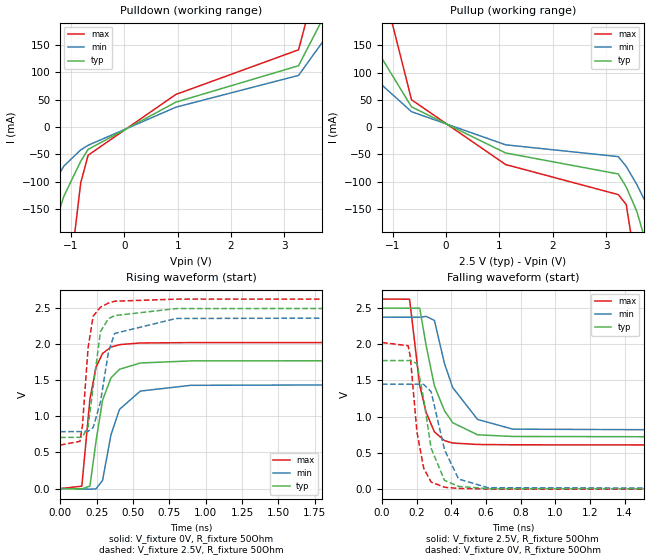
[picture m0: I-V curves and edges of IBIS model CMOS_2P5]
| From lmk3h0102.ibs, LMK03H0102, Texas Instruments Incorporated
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[Model]   CMOS_2P5
Model_type   Output
Polarity   Non-Inverting
Vmeas = 1.25
Vref = 0
Cref = 5pF
Rref = 100000
|   typ   min   max
C_comp   2.5pF   2pF   3pF
[Voltage Range]   2.5   2.375   2.625
[Temperature Range]   45   125   -40
[Pullup Reference]   2.5   2.375   2.625
[Pulldown Reference]   0   0   0
[Power Clamp Reference]   2.5   2.375   2.625
[GND Clamp Reference]   0   0   0
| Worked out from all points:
|   slope of the pulldown table from 0 to 0.375 V, typ, clamps not added: 18.7 ohm
|   slope of the pullup table from 0 to 0.375 V, typ, clamps not added: 19.6 ohm
|   falling waveform, V_fixture 2.5V, R_fixture 50Ohm: 20-80 % time 120ps typ, 157ps min, 83.9ps max; typ from 2.5 V to 0.708 V
|   rising waveform, V_fixture 0V, R_fixture 50Ohm: 20-80 % time 91.9ps typ, 118ps min, 70.2ps max; typ from 0 V to 1.77 V
|   rising waveform, V_fixture 2.5V, R_fixture 50Ohm: 20-80 % time 63.8ps typ, 86.2ps min, 48.1ps max; typ from 0.708 V to 2.5 V
|   falling waveform, V_fixture 0V, R_fixture 50Ohm: 20-80 % time 75.8ps typ, 91.7ps min, 57.9ps max; typ from 1.77 V to 0 V
[Pulldown]
|   Voltage   I(typ)   I(min)   I(max)
-3.3V     -897.3mA   -527.2mA   -2.687A
-2.221V   -519.5mA   -296.6mA   -1.529A
-1.34V    -191.4mA   -106.5mA   -555.5mA
-1.132V   -126.7mA   -71.27mA   -363.4mA
-815.1mV  -62.38mA   -41.6mA    -101.9mA
-676.5mV  -40.69mA   -33.18mA   -51.39mA
966.9mV   45.66mA    36.48mA    59.79mA
3.264V    112.3mA    94.6mA     141.4mA
3.749V    204.3mA    160.5mA    319.6mA
4.135V    293.1mA    223.3mA    516.9mA
5.402V    600.8mA    442.5mA    1.202A
6.6V      903.3mA    672mA      1.862A
[Pullup]
|   Voltage   I(typ)   I(min)   I(max)
-3.3V     606.4mA    421.4mA    1.361A
-2.538V   422.8mA    287mA      953.3mA
-1.825V   260mA      169.8mA    583.3mA
-1.181V   122.8mA    75.4mA     257.7mA
-646.8mV  37.13mA    28.31mA    50.19mA
1.115V    -47.36mA   -32.4mA    -68.56mA
3.224V    -85.87mA   -54.05mA   -123.7mA
3.373V    -109.6mA   -71.9mA    -141.8mA
3.571V    -154.2mA   -105.1mA   -264.3mA
3.937V    -277.2mA   -176.8mA   -616.1mA
4.749V    -584.9mA   -358mA     -1.516A
6.6V      -1.309A    -817.2mA   -3.598A
[Ramp]
R_load = 50
|   typ   min   max
dV/dt_r   1.06504/9.18916e-11   0.869589/1.17448e-10   1.21419/6.98564e-11
dV/dt_f   1.07469/1.19617e-10   0.951604/1.56694e-10   1.21291/8.3962e-11
[Falling Waveform]
V_fixture = 2.5V
V_fixture_min = 2.375V
V_fixture_max = 2.625V
R_fixture = 50Ohm
C_fixture = 0F
|   Time   V(typ)   V(min)   V(max)
0s        2.499V     2.374V     2.624V
159.3ps   2.498V     2.373V     2.622V
217.8ps   2.498V     2.373V     1.43V
255.2ps   1.977V     2.385V     1.057V
302.6ps   1.425V     2.329V     790.7mV
360.5ps   1.084V     1.734V     670.3mV
408.2ps   917.3mV    1.402V     636.8mV
551.5ps   750.2mV    962.5mV    617mV
755ps     727.4mV    828.3mV    612.3mV
5ns       707.9mV    787.7mV    602.6mV
[Rising Waveform]
V_fixture = 0V
V_fixture_min = 0V
V_fixture_max = 0V
R_fixture = 50Ohm
C_fixture = 0F
|   Time   V(typ)   V(min)   V(max)
0s        114.4uV    4.884uV    29.28uV
149ps     -4.508mV   -5.851mV   33.74mV
204.7ps   34.28mV    -8.041mV   1.238V
246.5ps   655.1mV    -3.982mV   1.681V
291.5ps   1.223V     112.2mV    1.871V
349.3ps   1.533V     744.1mV    1.959V
408.2ps   1.652V     1.097V     1.993V
551.5ps   1.739V     1.35V      2.016V
899.5ps   1.768V     1.43V      2.021V
5ns       1.775V     1.449V     2.024V
[Rising Waveform]
V_fixture = 2.5V
V_fixture_min = 2.375V
V_fixture_max = 2.625V
R_fixture = 50Ohm
C_fixture = 0F
|   Time   V(typ)   V(min)   V(max)
0s        707.9mV    787.8mV    602.6mV
136.3ps   709.7mV    789.9mV    653.9mV
153.1ps   713.2mV    790.2mV    865.9mV
191.8ps   856.2mV    792.7mV    1.947V
227ps     1.407V     844.7mV    2.388V
277.2ps   2.173V     1.2V       2.512V
331.9ps   2.351V     1.889V     2.568V
374.3ps   2.395V     2.148V     2.594V
797ps     2.492V     2.355V     2.623V
5ns       2.499V     2.374V     2.624V
[Falling Waveform]
|Gnd
V_fixture = 0V
V_fixture_min = 0V
V_fixture_max = 0V
R_fixture = 50Ohm
C_fixture = 0F
|   Time   V(typ)   V(min)   V(max)
0s        1.775V     1.449V     2.024V
151ps     1.775V     1.449V     1.98V
163.6ps   1.775V     1.449V     1.826V
201.7ps   1.735V     1.449V     788.6mV
240.6ps   1.243V     1.446V     289.7mV
283.5ps   565.1mV    1.346V     98.25mV
361ps     121mV      542.1mV    26.37mV
442.3ps   38.17mV    139.4mV    10.06mV
612.2ps   6.67mV     20.15mV    1.842mV
5ns       115uV      4.884uV    29.1uV
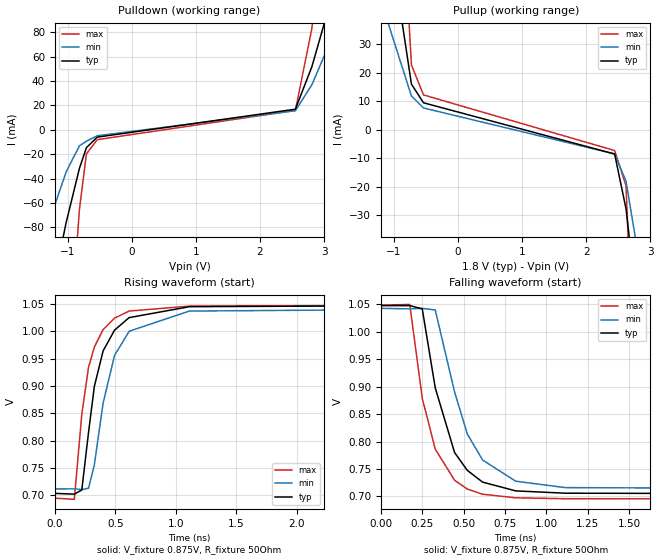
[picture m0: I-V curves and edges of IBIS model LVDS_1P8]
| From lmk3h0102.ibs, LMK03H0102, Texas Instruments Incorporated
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[Model]   LVDS_1P8
Model_type   Output
Polarity   Non-Inverting
Vmeas = 0.875
Vref = 0.875
Cref = 2pF
Rref = 50
|   typ   min   max
C_comp   2.5pF   2pF   3pF
[Voltage Range]   1.8   1.71   1.89
[Temperature Range]   45   125   -40
[Pullup Reference]   1.8   1.71   1.89
[Pulldown Reference]   -0   -0   -0
[Power Clamp Reference]   1.8   1.71   1.89
[GND Clamp Reference]   0   0   0
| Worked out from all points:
|   slope of the pulldown table from 0 to 0.27 V, typ, clamps not added: 203 ohm
|   slope of the pullup table from 0 to 0.27 V, typ, clamps not added: 98.5 ohm
|   falling waveform, V_fixture 0.875V, R_fixture 50Ohm: 20-80 % time 172ps typ, 197ps min, 152ps max; typ from 1.05 V to 0.703 V
|   rising waveform, V_fixture 0.875V, R_fixture 50Ohm: 20-80 % time 170ps typ, 196ps min, 145ps max; typ from 0.703 V to 1.05 V
[Pulldown]
|   Voltage   I(typ)   I(min)   I(max)
-3.3V     -894.5mA   -522.3mA   -2.693A
-1.924V   -376.8mA   -199.3mA   -1.167A
-1.201V   -121.6mA   -61.92mA   -389.7mA
-1.023V   -76.22mA   -34.6mA    -216.5mA
-815.1mV  -31.51mA   -13.12mA   -64.98mA
-706.2mV  -14.63mA   -9.426mA   -19.76mA
-537.9mV  -6.062mA   -4.944mA   -8.138mA
2.551V    16.85mA    15.59mA    15.87mA
2.808V    51.65mA    36.84mA    83.06mA
2.996V    86.16mA    60.01mA    166.7mA
3.373V    162.5mA    112.9mA    348.7mA
6.6V      964mA      720.1mA    2.099A
[Pullup]
|   Voltage   I(typ)   I(min)   I(max)
-3.3V     557.9mA    396.7mA    1.299A
-1.607V   174.9mA    107.5mA    423mA
-1.171V   85.98mA    47.27mA    207.2mA
-1.092V   70.74mA    37.67mA    169.3mA
-726mV    16.02mA    11.86mA    22.73mA
-537.9mV  9.466mA    7.645mA    12.23mA
2.442V    -8.531mA   -8.492mA   -7.311mA
2.62V     -27.84mA   -18.14mA   -19.72mA
2.808V    -65.39mA   -43.81mA   -125.9mA
2.957V    -104.7mA   -67.69mA   -247.2mA
3.184V    -180.4mA   -108mA     -475.1mA
6.6V      -1.532A    -938.1mA   -4.374A
[Ramp]
R_load = 50
|   typ   min   max
dV/dt_r   0.207102/1.69149e-10   0.198775/1.94703e-10   0.212527/1.45266e-10
dV/dt_f   0.207098/1.71548e-10   0.198779/1.96697e-10   0.212514/1.51805e-10
[Falling Waveform]
V_fixture = 0.875V
V_fixture_min = 0.875V
V_fixture_max = 0.875V
R_fixture = 50Ohm
C_fixture = 0F
|   Time   V(typ)   V(min)   V(max)
0s        1.048V     1.043V     1.049V
173.8ps   1.048V     1.042V     1.05V
249.3ps   1.042V     1.043V     879mV
327.8ps   897.9mV    1.04V      786.1mV
444.7ps   779.9mV    890.5mV    729.3mV
521.5ps   747.4mV    813.9mV    713.3mV
614.2ps   725.9mV    766.2mV    703.8mV
814.5ps   709.9mV    727.6mV    697.3mV
1.113ns   705.7mV    715.9mV    695.6mV
5ns       703.3mV    711.5mV    694.5mV
[Rising Waveform]
V_fixture = 0.875V
V_fixture_min = 0.875V
V_fixture_max = 0.875V
R_fixture = 50Ohm
C_fixture = 0F
|   Time   V(typ)   V(min)   V(max)
0s        703.3mV    711.5mV    694.5mV
161.6ps   701.9mV    711.6mV    692.4mV
223.3ps   709.5mV    710.2mV    848.1mV
278.5ps   814.2mV    712.7mV    933.4mV
327ps     899.2mV    755.4mV    971.2mV
399.4ps   964.1mV    868.6mV    1.003V
493.6ps   1.002V     955.7mV    1.024V
614.2ps   1.025V     1V         1.037V
1.113ns   1.045V     1.037V     1.046V
5ns       1.049V     1.043V     1.049V
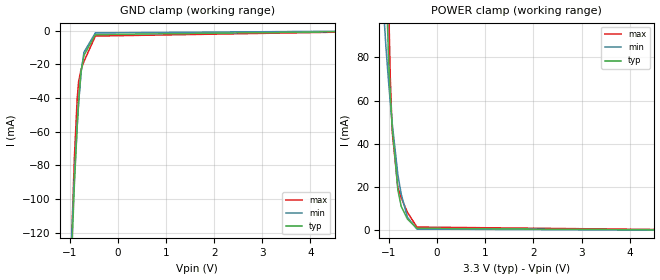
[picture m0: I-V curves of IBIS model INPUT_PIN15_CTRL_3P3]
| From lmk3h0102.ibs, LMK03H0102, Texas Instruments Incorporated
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[Model]   INPUT_PIN15_CTRL_3P3
Model_type   Input
Vinl = 0.4
Vinh = 2.145
|   typ   min   max
C_comp   0.7pF   0.5pF   0.9pF
[Voltage Range]   3.3   3.135   3.465
[Temperature Range]   45   125   -40
[Power Clamp Reference]   3.3   3.135   3.465
[GND Clamp Reference]   0   0   0
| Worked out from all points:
|   GND clamp passes 1 mA (typ) near -0.41 V on its own axis
|   POWER clamp passes 1 mA (typ) near -0.42 V on its own axis
[GND Clamp]
|   Voltage   I(typ)   I(min)   I(max)
-3.3V     -2.474A    -2.191A    -2.782A
-1.132V   -277.9mA   -243.6mA   -280mA
-1.043V   -198.1mA   -176.1mA   -194.8mA
-1.033V   -189.6mA   -169mA     -185.7mA
-1.013V   -173mA     -155.2mA   -167.6mA
-904.2mV  -91.28mA   -86.97mA   -75.43mA
-844.8mV  -56.1mA    -55.89mA   -39.89mA
-815.1mV  -41.69mA   -42.5mA    -30.02mA
-765.6mV  -24.25mA   -24.86mA   -23.17mA
-706.2mV  -14.74mA   -12.92mA   -18.37mA
-468.6mV  -2.382mA   -1.374mA   -3.243mA
6.6V      0A         0A         0A
[POWER Clamp]
|   Voltage   I(typ)   I(min)   I(max)
-3.3V     4.358A     3.47A      5.491A
-1.102V   157.7mA    98.45mA    260.4mA
-1.063V   117.7mA    84.69mA    188.7mA
-1.013V   82.15mA    70.06mA    113.5mA
-1.003V   76.72mA    67.34mA    101.2mA
-973.5mV  62.88mA    59.5mA     70.99mA
-933.9mV  48.27mA    49.68mA    45.88mA
-815.1mV  18.76mA    25.75mA    19.77mA
-745.8mV  11.11mA    16.79mA    15.13mA
-617.1mV  5.305mA    6.137mA    8.372mA
-419.1mV  967.2uA    633.2uA    1.571mA
6.6V      0A         0A         0A
